VERSION 5.8 ;
BUSBITCHARS "[]" ;
DIVIDERCHAR "/" ;
UNITS
    DATABASE MICRONS 1000 ;
END UNITS

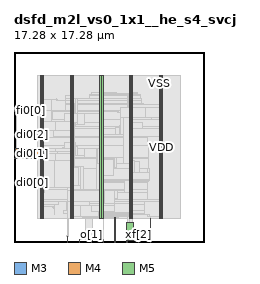
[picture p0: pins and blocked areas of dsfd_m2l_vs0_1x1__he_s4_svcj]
MACRO dsfd_m2l_vs0_1x1__he_s4_svcj
  FOREIGN dsfd_m2l_vs0_1x1__he_s4_svcj 0 0 ;
  CLASS BLOCK ;
  SIZE 17.28 BY 17.28 ;
  PIN ck[0]
    DIRECTION INPUT ;
    USE SIGNAL ;
    PORT
      LAYER M3 ;
        RECT  4.86 0 4.878 0.144 ;
    END
    PORT
      LAYER M3 ;
        RECT  4.86 0.108 4.878 0.52 ;
    END
  END ck[0]
  PIN di0[0]
    DIRECTION INPUT ;
    USE SIGNAL ;
    PORT
      LAYER M4 ;
        RECT  0 5.424 0.192 5.448 ;
    END
    PORT
      LAYER M4 ;
        RECT  0.156 5.424 2.408 5.448 ;
    END
  END di0[0]
  PIN di0[1]
    DIRECTION INPUT ;
    USE SIGNAL ;
    PORT
      LAYER M4 ;
        RECT  0 7.584 0.192 7.608 ;
    END
    PORT
      LAYER M4 ;
        RECT  0.156 7.584 0.181 7.608 ;
    END
    PORT
      LAYER M4 ;
        RECT  0.181 7.584 2.408 8.52 ;
    END
  END di0[1]
  PIN di0[2]
    DIRECTION INPUT ;
    USE SIGNAL ;
    PORT
      LAYER M4 ;
        RECT  0 9.744 0.192 9.768 ;
    END
    PORT
      LAYER M4 ;
        RECT  0.156 9.744 2.408 9.768 ;
    END
  END di0[2]
  PIN fi0[0]
    DIRECTION INPUT ;
    USE SIGNAL ;
    PORT
      LAYER M4 ;
        RECT  0 11.904 0.192 11.928 ;
    END
    PORT
      LAYER M4 ;
        RECT  0.156 11.904 0.227 11.928 ;
    END
  END fi0[0]
  PIN o[0]
    DIRECTION OUTPUT ;
    USE SIGNAL ;
    PORT
      LAYER M5 ;
        RECT  5.952 0 5.976 0.192 ;
    END
    PORT
      LAYER M5 ;
        RECT  5.952 0.144 5.976 0.227 ;
    END
  END o[0]
  PIN o[1]
    DIRECTION OUTPUT ;
    USE SIGNAL ;
    PORT
      LAYER M3 ;
        RECT  7.02 0 7.038 0.144 ;
    END
    PORT
      LAYER M3 ;
        RECT  7.02 0.108 7.038 0.139 ;
    END
    PORT
      LAYER M3 ;
        RECT  7.02 0.139 7.11 0.187 ;
    END
  END o[1]
  PIN rs[0]
    DIRECTION INPUT ;
    USE SIGNAL ;
    PORT
      LAYER M5 ;
        RECT  8.112 0 8.136 0.192 ;
    END
    PORT
      LAYER M5 ;
        RECT  8.112 0.144 8.136 0.227 ;
    END
  END rs[0]
  PIN xf[0]
    DIRECTION INPUT ;
    USE SIGNAL ;
    PORT
      LAYER M3 ;
        RECT  9.18 0 9.198 0.144 ;
    END
    PORT
      LAYER M3 ;
        RECT  9.18 0.108 9.198 2.227 ;
    END
  END xf[0]
  PIN xf[1]
    DIRECTION INPUT ;
    USE SIGNAL ;
    PORT
      LAYER M5 ;
        RECT  10.272 0 10.296 0.192 ;
    END
    PORT
      LAYER M5 ;
        RECT  10.272 0.144 10.824 1.763 ;
    END
  END xf[1]
  PIN xf[2]
    DIRECTION INPUT ;
    USE SIGNAL ;
    PORT
      LAYER M3 ;
        RECT  11.34 0 11.358 0.144 ;
    END
    PORT
      LAYER M3 ;
        RECT  11.34 0.108 11.358 0.173 ;
    END
  END xf[2]
  PIN xf[3]
    DIRECTION INPUT ;
    USE SIGNAL ;
    PORT
      LAYER M5 ;
        RECT  12.384 0 12.408 0.192 ;
    END
    PORT
      LAYER M5 ;
        RECT  12.384 0.144 12.408 2.137 ;
    END
  END xf[3]
  PIN VDD
    DIRECTION INOUT ;
    USE POWER ;
    PORT
      LAYER M5 ;
        RECT  13.392 2.151 13.512 15.129 ;
        RECT  10.692 2.151 10.812 15.129 ;
        RECT  7.992 2.151 8.112 15.129 ;
        RECT  5.292 2.151 5.412 15.129 ;
        RECT  2.592 2.151 2.712 15.129 ;
    END
  END VDD
  PIN VSS
    DIRECTION INOUT ;
    USE GROUND ;
    PORT
      LAYER M5 ;
        RECT  13.2 2.137 13.32 15.143 ;
        RECT  10.5 2.137 10.62 15.143 ;
        RECT  7.8 2.137 7.92 15.143 ;
        RECT  5.1 2.137 5.22 15.143 ;
        RECT  2.4 2.137 2.52 15.143 ;
    END
  END VSS
  # OT_OBS_CLOSED layer=M5 d_um=1.536 added=14
  OBS
    LAYER RVTN ;
     RECT  2.16 2.16 15.12 2.295 ;
     RECT  2.16 2.565 15.12 2.835 ;
     RECT  2.16 3.105 15.12 3.375 ;
     RECT  2.16 3.645 15.12 3.915 ;
     RECT  2.16 4.185 15.12 4.455 ;
     RECT  2.16 4.725 15.12 4.995 ;
     RECT  2.16 5.265 15.12 5.535 ;
     RECT  2.16 5.805 15.12 6.075 ;
     RECT  2.16 6.345 15.12 6.615 ;
     RECT  2.16 6.885 15.12 7.155 ;
     RECT  2.16 7.425 15.12 7.695 ;
     RECT  2.16 7.965 15.12 8.235 ;
     RECT  2.16 8.505 15.12 8.775 ;
     RECT  2.16 9.045 15.12 9.315 ;
     RECT  2.16 9.585 15.12 9.855 ;
     RECT  2.16 10.125 15.12 10.395 ;
     RECT  2.16 10.665 15.12 10.935 ;
     RECT  2.16 11.205 15.12 11.475 ;
     RECT  2.16 11.745 15.12 12.015 ;
     RECT  2.16 12.285 15.12 12.555 ;
     RECT  2.16 12.825 15.12 13.095 ;
     RECT  2.16 13.365 15.12 13.635 ;
     RECT  2.16 13.905 15.12 14.175 ;
     RECT  2.16 14.445 15.12 14.715 ;
     RECT  2.16 14.985 15.12 15.12 ;
    LAYER RVTP ;
     RECT  2.16 2.295 15.12 2.565 ;
     RECT  2.16 2.835 15.12 3.105 ;
     RECT  2.16 3.375 15.12 3.645 ;
     RECT  2.16 3.915 15.12 4.185 ;
     RECT  2.16 4.455 15.12 4.725 ;
     RECT  2.16 4.995 15.12 5.265 ;
     RECT  2.16 5.535 15.12 5.805 ;
     RECT  2.16 6.075 15.12 6.345 ;
     RECT  2.16 6.615 15.12 6.885 ;
     RECT  2.16 7.155 15.12 7.425 ;
     RECT  2.16 7.695 15.12 7.965 ;
     RECT  2.16 8.235 15.12 8.505 ;
     RECT  2.16 8.775 15.12 9.045 ;
     RECT  2.16 9.315 15.12 9.585 ;
     RECT  2.16 9.855 15.12 10.125 ;
     RECT  2.16 10.395 15.12 10.665 ;
     RECT  2.16 10.935 15.12 11.205 ;
     RECT  2.16 11.475 15.12 11.745 ;
     RECT  2.16 12.015 15.12 12.285 ;
     RECT  2.16 12.555 15.12 12.825 ;
     RECT  2.16 13.095 15.12 13.365 ;
     RECT  2.16 13.635 15.12 13.905 ;
     RECT  2.16 14.175 15.12 14.445 ;
     RECT  2.16 14.715 15.12 14.985 ;
    LAYER M1 ;
     RECT  2.16 2.151 15.12 15.129 ;
    LAYER M2 ;
     RECT  4.783 0.531 4.883 0.549 ;
     RECT  7.015 0.144 7.115 0.162 ;
     RECT  2.16 2.151 15.12 15.129 ;
    LAYER M3 ;
     RECT  4.788 0.52 4.878 0.554 ;
     RECT  4.788 0.554 4.806 0.557 ;
     RECT  6.516 0.187 7.11 2.143 ;
     RECT  8.136 0.187 8.154 2.143 ;
     RECT  6.516 2.143 8.154 2.191 ;
     RECT  6.264 2.191 8.154 2.227 ;
     RECT  6.264 2.227 9.198 2.263 ;
     RECT  6.264 2.263 9.486 2.299 ;
     RECT  10.296 1.723 10.818 2.299 ;
     RECT  5.976 2.299 10.818 2.335 ;
     RECT  5.115 2.143 5.205 2.371 ;
     RECT  5.94 2.335 10.818 2.371 ;
     RECT  2.415 2.143 2.505 2.413 ;
     RECT  13.215 2.143 13.305 2.413 ;
     RECT  12.168 2.299 12.33 2.489 ;
     RECT  5.115 2.371 10.818 2.497 ;
     RECT  12.168 2.489 12.186 2.497 ;
     RECT  11.7 2.497 12.186 2.525 ;
     RECT  5.115 2.497 10.854 2.533 ;
     RECT  11.7 2.525 11.826 2.533 ;
     RECT  5.115 2.533 11.826 2.569 ;
     RECT  4.5 2.569 11.826 2.861 ;
     RECT  3.672 2.461 3.69 3.073 ;
     RECT  3.564 3.073 3.69 3.145 ;
     RECT  2.415 2.413 2.697 3.271 ;
     RECT  3.528 3.145 3.69 3.271 ;
     RECT  4.752 2.861 11.826 3.407 ;
     RECT  2.415 3.271 3.69 3.451 ;
     RECT  2.415 3.451 4.014 3.685 ;
     RECT  4.752 3.407 6.21 3.685 ;
     RECT  6.984 3.407 11.826 3.685 ;
     RECT  6.984 3.685 11.97 3.721 ;
     RECT  13.215 2.413 13.497 3.721 ;
     RECT  2.415 3.685 6.21 3.839 ;
     RECT  6.984 3.721 13.497 3.839 ;
     RECT  6.984 3.839 12.15 4.495 ;
     RECT  2.415 3.839 6.03 4.765 ;
     RECT  6.912 4.495 12.15 4.765 ;
     RECT  2.415 4.765 12.15 5.419 ;
     RECT  2.304 5.419 12.15 5.467 ;
     RECT  2.304 5.467 12.222 5.495 ;
     RECT  2.34 5.495 12.222 5.611 ;
     RECT  2.34 5.611 12.366 5.729 ;
     RECT  2.415 5.729 12.366 6.719 ;
     RECT  2.415 6.719 12.258 7.579 ;
     RECT  2.304 7.579 12.258 7.655 ;
     RECT  2.415 7.655 12.258 7.691 ;
     RECT  2.415 7.691 12.222 8.771 ;
     RECT  2.415 8.771 12.15 9.509 ;
     RECT  3.636 9.509 12.15 9.625 ;
     RECT  13.215 3.839 13.497 9.625 ;
     RECT  2.415 9.509 2.697 9.739 ;
     RECT  2.304 9.739 2.697 9.815 ;
     RECT  3.636 9.625 13.497 10.291 ;
     RECT  2.415 9.815 2.697 10.459 ;
     RECT  3.492 10.291 13.497 10.459 ;
     RECT  2.415 10.459 13.497 10.499 ;
     RECT  3.42 10.499 13.497 11.165 ;
     RECT  2.415 10.499 2.697 11.911 ;
     RECT  3.528 11.165 12.474 11.911 ;
     RECT  13.215 11.165 13.497 11.911 ;
     RECT  2.415 11.911 13.497 11.939 ;
     RECT  4.248 11.939 13.497 11.975 ;
     RECT  2.415 11.939 3.258 11.981 ;
     RECT  4.644 11.975 13.497 12.479 ;
     RECT  4.644 12.479 12.474 12.515 ;
     RECT  4.644 12.515 11.754 12.551 ;
     RECT  4.644 12.551 11.574 12.856 ;
     RECT  4.248 12.856 11.574 12.865 ;
     RECT  3.888 12.865 11.574 12.893 ;
     RECT  3.888 12.893 3.906 13.019 ;
     RECT  4.68 12.893 11.574 13.055 ;
     RECT  4.68 13.055 11.538 13.085 ;
     RECT  4.68 13.085 5.706 13.091 ;
     RECT  4.68 13.091 5.397 13.289 ;
     RECT  6.84 13.085 11.538 13.289 ;
     RECT  4.86 13.289 5.397 13.325 ;
     RECT  10.188 13.289 11.538 13.325 ;
     RECT  10.188 13.325 11.466 13.397 ;
     RECT  6.84 13.289 9.342 13.433 ;
     RECT  10.188 13.397 11.25 13.469 ;
     RECT  7.056 13.433 9.342 13.559 ;
     RECT  10.515 13.469 11.25 13.559 ;
     RECT  10.515 13.559 11.106 13.595 ;
     RECT  2.415 11.981 2.697 14.867 ;
     RECT  5.115 13.325 5.397 14.867 ;
     RECT  7.815 13.559 8.097 14.867 ;
     RECT  10.515 13.595 10.797 14.867 ;
     RECT  13.215 12.479 13.497 14.867 ;
     RECT  2.415 14.867 2.505 15.137 ;
     RECT  5.115 14.867 5.205 15.137 ;
     RECT  7.815 14.867 7.905 15.137 ;
     RECT  10.515 14.867 10.605 15.137 ;
     RECT  13.215 14.867 13.305 15.137 ;
    LAYER M4 ;
     RECT  2.408 2.148 2.512 15.132 ;
     RECT  2.512 2.418 2.704 14.862 ;
     RECT  2.704 4.512 2.819 8.52 ;
     RECT  2.704 11.952 3.443 11.976 ;
     RECT  2.819 4.944 3.683 8.52 ;
     RECT  2.704 10.464 3.781 10.92 ;
     RECT  3.781 10.176 3.868 10.92 ;
     RECT  2.704 12.96 3.917 12.984 ;
     RECT  3.683 5.136 4.025 8.52 ;
     RECT  4.025 6.24 4.417 8.52 ;
     RECT  4.417 6.24 4.561 8.568 ;
     RECT  3.868 10.896 4.561 10.92 ;
     RECT  4.025 5.136 4.885 5.16 ;
     RECT  4.777 0.528 4.931 0.552 ;
     RECT  4.489 2.832 5.108 2.856 ;
     RECT  4.885 4.656 5.108 5.16 ;
     RECT  4.561 6.24 5.108 9.048 ;
     RECT  4.561 10.896 5.108 11.688 ;
     RECT  4.237 12.864 5.108 12.888 ;
     RECT  5.108 2.148 5.212 15.132 ;
     RECT  5.212 2.304 5.404 14.862 ;
     RECT  5.404 10.608 5.555 13.08 ;
     RECT  5.404 7.872 5.573 9.048 ;
     RECT  5.573 7.872 5.753 8.664 ;
     RECT  5.555 10.704 5.789 13.08 ;
     RECT  5.404 2.304 6.076 6.84 ;
     RECT  6.076 4.656 6.329 6.84 ;
     RECT  5.789 10.704 6.401 11.688 ;
     RECT  5.753 7.872 6.433 8.52 ;
     RECT  5.941 0.192 6.545 0.216 ;
     RECT  6.329 4.656 7.477 6.696 ;
     RECT  6.433 7.68 7.477 8.52 ;
     RECT  6.076 2.304 7.669 3.336 ;
     RECT  7.669 2.256 7.808 3.336 ;
     RECT  7.477 4.656 7.808 8.52 ;
     RECT  6.401 10.848 7.808 11.688 ;
     RECT  5.789 13.056 7.808 13.08 ;
     RECT  7.808 2.148 7.912 15.132 ;
     RECT  7.912 2.256 8.104 14.862 ;
     RECT  8.081 0.192 8.165 0.216 ;
     RECT  8.104 2.256 8.201 4.776 ;
     RECT  8.201 2.256 8.243 4.68 ;
     RECT  8.104 6.048 9.065 7.464 ;
     RECT  8.243 2.688 9.148 4.68 ;
     RECT  9.065 6.816 9.169 7.464 ;
     RECT  8.104 9.744 9.241 9.768 ;
     RECT  9.169 6.816 9.281 7.656 ;
     RECT  9.148 3.984 9.389 4.68 ;
     RECT  9.148 2.688 9.425 2.856 ;
     RECT  9.457 11.76 9.529 11.784 ;
     RECT  9.241 9.744 9.565 10.44 ;
     RECT  9.565 9.744 9.685 10.632 ;
     RECT  9.529 11.76 9.685 11.976 ;
     RECT  9.389 4.512 10.033 4.68 ;
     RECT  9.281 7.152 10.357 7.656 ;
     RECT  9.685 9.744 10.357 12.264 ;
     RECT  8.104 13.44 10.357 13.464 ;
     RECT  10.241 1.728 10.508 1.752 ;
     RECT  9.425 2.832 10.508 2.856 ;
     RECT  10.033 4.512 10.508 5.592 ;
     RECT  10.357 7.152 10.508 8.472 ;
     RECT  10.357 9.744 10.508 13.464 ;
     RECT  10.508 1.728 10.612 15.132 ;
     RECT  10.612 1.728 10.804 14.862 ;
     RECT  10.804 11.952 10.865 12.264 ;
     RECT  10.804 1.728 10.873 1.752 ;
     RECT  10.804 6.336 10.937 7.416 ;
     RECT  10.789 0.144 11.369 0.168 ;
     RECT  10.937 6.336 11.441 7.32 ;
     RECT  10.865 12.24 11.441 12.264 ;
     RECT  10.804 10.32 11.729 10.872 ;
     RECT  11.729 10.32 11.873 10.344 ;
     RECT  11.9 12.192 11.941 12.216 ;
     RECT  11.941 11.376 11.987 12.216 ;
     RECT  11.987 11.376 12.053 11.4 ;
     RECT  11.441 6.336 12.125 6.648 ;
     RECT  12.125 6.336 12.197 6.36 ;
     RECT  12.157 2.304 13.208 2.328 ;
     RECT  13.208 2.148 13.312 15.132 ;
     RECT  13.312 2.418 13.504 14.862 ;
    LAYER M5 ;
     RECT  10.8 0.133 10.824 0.144 ;
     RECT  4.896 0.517 4.92 2.137 ;
     RECT  2.4 2.137 2.52 2.151 ;
     RECT  4.896 2.137 5.22 2.151 ;
     RECT  7.8 2.137 7.92 2.151 ;
     RECT  12.384 2.137 13.32 2.151 ;
     RECT  7.8 2.151 8.112 2.245 ;
     RECT  12.384 2.151 13.512 2.339 ;
     RECT  7.68 2.245 8.232 2.677 ;
     RECT  7.68 2.677 9.096 2.773 ;
     RECT  7.008 2.773 9.096 3.301 ;
     RECT  6.864 3.301 9.096 3.539 ;
     RECT  4.896 2.151 5.412 3.685 ;
     RECT  6.864 3.539 8.112 3.685 ;
     RECT  2.4 2.151 2.712 4.501 ;
     RECT  4.896 3.685 8.112 4.691 ;
     RECT  5.1 4.691 8.112 4.787 ;
     RECT  2.4 4.501 2.808 4.933 ;
     RECT  5.1 4.787 6.024 5.171 ;
     RECT  5.1 5.171 5.832 6.755 ;
     RECT  7.8 4.787 8.112 7.141 ;
     RECT  10.5 1.763 10.812 7.141 ;
     RECT  2.4 4.933 3.672 7.381 ;
     RECT  2.4 7.381 3.768 8.053 ;
     RECT  2.4 8.053 3.96 8.195 ;
     RECT  5.1 6.755 5.412 8.197 ;
     RECT  3.744 8.195 3.96 8.243 ;
     RECT  3.744 8.243 3.768 8.531 ;
     RECT  7.632 7.141 8.112 8.531 ;
     RECT  5.1 8.197 5.544 10.837 ;
     RECT  3.792 10.165 3.816 10.931 ;
     RECT  9.984 7.141 10.812 11.317 ;
     RECT  5.1 10.837 5.736 11.699 ;
     RECT  0.192 8.485 0.216 11.939 ;
     RECT  2.4 8.195 2.712 11.941 ;
     RECT  11.952 11.365 11.976 12.227 ;
     RECT  9.696 11.317 10.812 12.275 ;
     RECT  5.1 11.699 5.544 12.563 ;
     RECT  2.4 11.941 3.432 12.995 ;
     RECT  10.368 12.275 10.812 13.475 ;
     RECT  2.4 12.995 2.712 15.129 ;
     RECT  5.1 12.563 5.412 15.129 ;
     RECT  7.8 8.531 8.112 15.129 ;
     RECT  10.5 13.475 10.812 15.129 ;
     RECT  13.2 2.339 13.512 15.129 ;
     RECT  2.4 15.129 2.52 15.143 ;
     RECT  5.1 15.129 5.22 15.143 ;
     RECT  7.8 15.129 7.92 15.143 ;
     RECT  10.5 15.129 10.62 15.143 ;
     RECT  13.2 15.129 13.32 15.143 ;
     RECT  9.096 2.677 10.5 3.539 ;
     RECT  5.412 3.301 6.864 3.685 ;
     RECT  4.896 4.691 5.1 4.933 ;
     RECT  3.672 4.933 5.1 7.381 ;
     RECT  5.412 6.755 5.544 8.197 ;
     RECT  3.768 7.381 5.1 8.053 ;
     RECT  3.96 8.053 5.1 8.243 ;
     RECT  2.712 8.195 3.744 8.531 ;
     RECT  3.768 8.243 5.1 8.531 ;
     RECT  2.712 10.165 3.792 10.931 ;
     RECT  3.816 10.165 5.1 10.931 ;
     RECT  2.712 10.931 3.432 11.941 ;
     RECT  10.812 11.365 11.952 12.227 ;
     RECT  11.976 11.365 13.2 12.227 ;
  END
END dsfd_m2l_vs0_1x1__he_s4_svcj
END LIBRARY
